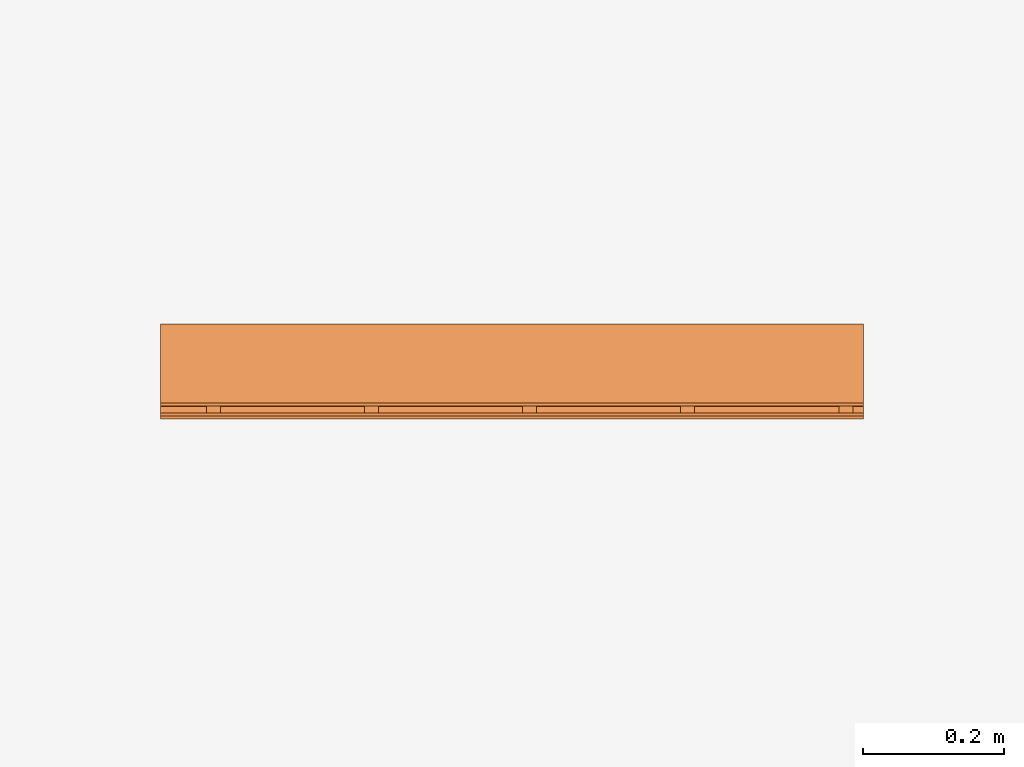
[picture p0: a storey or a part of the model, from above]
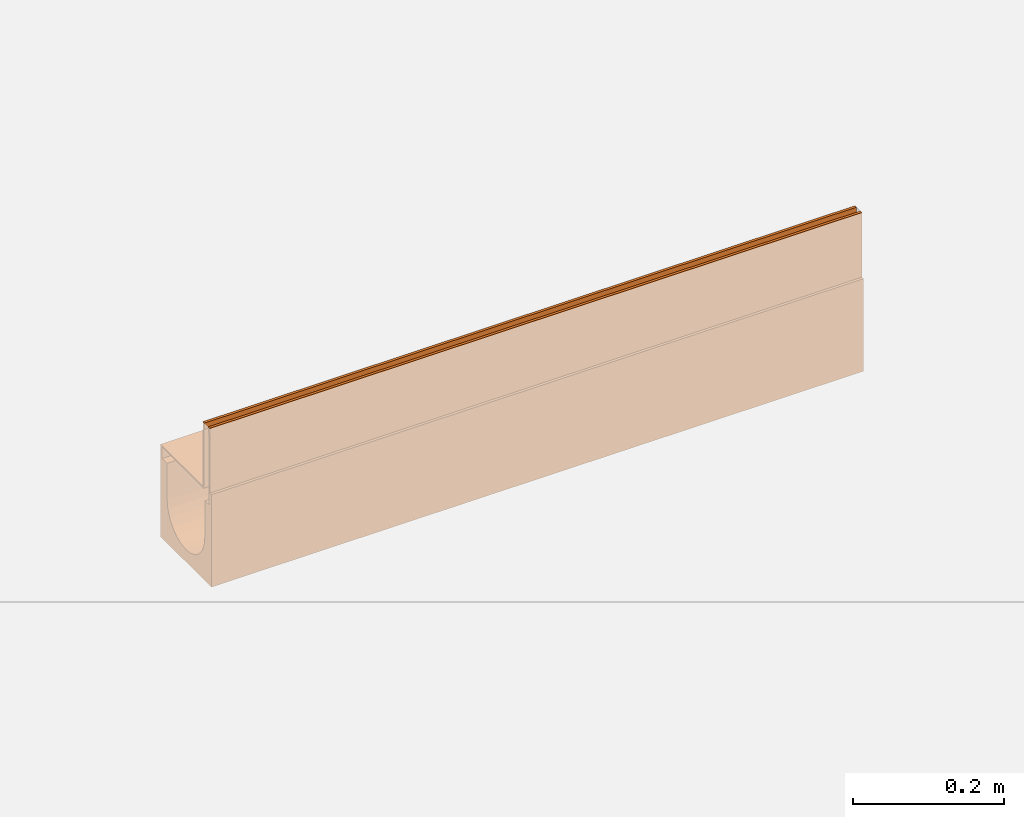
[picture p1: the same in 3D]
Properties of the parts of a building model (IFC2X3)

# File
Description: ViewDefinition [CoordinationView]
File name: 23000 - No 0.0 Constant Depth Channel - 1000mm LG - Invert Depth 130mm.ifc
Time: 2013-10-31T17:19:01
Written by: Autodesk Revit 2013
Made in: 20120221_2030(x64)

# IfcProject, Project Number
LongName: Project Name; Phase: Project Status

# IfcSite, Default
RefLatitude: 42, 21, 30, 344238; RefLongitude: -71, -3, -35, -194702; RefElevation: 0 mm

# IfcBuilding
Pset_BuildingCommon - NumberOfStoreys: 1
Other - Project Issue Date: Issue Date; Project Status: Project Status; Project Number: Project Number; Client Name: Owner; Project Name: Project Name; Project Address: ## Street City, State Zip

# IfcBuildingStorey, Level 1
LongName: Level 1; Elevation: 0 mm
Constraints - Elevation Base: 0; Elevation: 0 mm
Graphics - Line Weight: 1; Color: 0; Symbol at End 2 Default: yes; Symbol: M_Level Head - Circle: M_Level Head - Circle; Symbol at End 1 Default: no; Line Pattern: Center
Identity Data - Building Story: yes; Structural: no; Name: Level 1
Dimensions - Computation Height: 0 mm

# IfcBuildingElementProxy: 23000 - No 0.0 Constant Depth Channel - 1000mm LG - Invert Depth 130mm, Civil-Drainage-Channel-ACO-MultiDrain-M100D-Brickslot-Channel-System:23000 - No 0.0 Constant Depth Channel - 1000mm LG - Invert Depth 130mm:23000 - No 0.0 Constant Depth Channel - 1000mm LG - Invert Depth 130mm:196059
In: Level 1
Material: Steel, Galvanized, Vienite® Synthetic Resin Concrete
Phasing - Phase Created: New Construction
Constraints - Moves With Nearby Elements: no; Level: Level: Level 1
Construction - 23466_Load Class D400_Brickslot Grating_Galvanized Steel_500mm Long: no; 23461_Load Class C250_Brickslot Grating_Galvanized Steel_500mm Long: no; 23460_Load Class C250_Brickslot Grating_Galvanized Steel_1000mm Long: no; 23467_Load Class D400_Brickslot Access Unit_Galvanised Steel_500mm Long: no; 23462_Load Class C250_Brickslot Access Unit_Galvanised Steel_500mm Long: no; 23404_Universal Endcap (Male End): no; 23465_Load Class D400_Brickslot Grating_Galvanized Steel_1000mm Long: yes; 23404_Universal Endcap (Female End): no; Constant Depth Junction Channel: no; 23410_Sump Unit: no; Shallow Depth Channel with seal: no; Constant Depth Channel: yes; Sloping Channel: no; Shallow Depth Channel: no
Dimensions - FloorCut_Length: -1000 mm; Volume: 8492822 mm3; Brickslot Void Depth: 0 mm; Brickslot Access Unit Void Bottom Depth: -6605 mm; Brickslot Void Length: 1000 mm; Length: 1000 mm; EndCap Position: 1000 mm; Brickslot Access Unit Void Depth: -6500 mm; Custom_Void_length: 0 mm; ShallowOverallDepth: 100 mm; FloorCut_Width: 135 mm; Access_Custom_Void_Length: 0 mm; Length Drain: -1000 mm; Depth: 150 mm; InvDepth: 80 mm; Floor Cut Gap: 105 mm; SlopingEndOverallDepth: 250 mm; EndCap_Height: 150 mm; SlopingInvertDepth: 175 mm; SlopingEndInvertDepth: 180 mm; ShallowInvDepth: 80 mm; FloorCut_Depth: 150 mm; GratingLength: -1000 mm; Brickslot Access Unit Floor Cut Length: 500 mm; SlopingOverallDepth: 245 mm
Pset_BuildingElementProxyCommon - Reference: 23000 - No 0.0 Constant Depth Channel - 1000mm LG - Invert Depth 130mm
Identity Data - Product Page URL: http://www.aco.co.uk/product_detail.php?id=58; Product Code: 23000; Cost: 0; Watermarked With: BIM Manager Premium Suite; Manufacturer: ACO Technologies plc - ACO Water Management Division; e-mail Sales: customersupport@aco.co.uk; Price: POA - contact ACO; Assembly Code: D2040; Model Description: Channel drainage system; Fax: +44 (0)1462 815895; e-mail Technical: technical@aco.co.uk; Address: ACO Business Park, Hitchin Road, Shefford, Bedfordshire, United Kingdom SG17 5TE; Assembly Description: Rain Water Drainage; Product brochure: http://www.aco.co.uk/download.php?id=173; Watermark 1: This file is the property of ACO Technologies PLC; Maintenance guidelines: http://www.aco.co.uk/download.php?id=173; URL: www.aco.co.uk; Watermark 2: This file is water marked and users are prohibited to reproduce, adapt, distribute this information; Model: ACO MultiDrain MD Brickslot- M100D; Installation guidelines: http://www.aco.co.uk/download.php?id=173; Telephone: +44 (0)1462 816666; Type Comments: ACO MultiDrain M100D 0.0 Constant Depth Channel 1000mm Long; OmniClass Title: Rainwater Removal; OmniClass Number: 23.70.50.24
General - TagNumber: 0; SerialNumber: 0
Data - Product Dimensions: 1000mm x 135mm x 150mm (LxWxH); Hydraulic Performance: http://www.aco.co.uk/download.php?id=173; Concrete Surround Volume - Load Class D 400 - Concrete Pavement: 0.17m³/m; ACO Hydraulic Design Software: http://www.acodesign.co.uk; Concrete Surround Volume - Load Class B 125 - C 250 - Concrete Pavement: 0.11m³/m; Concrete Surround Volume - Load Class A 15 - Concrete Pavement: 0.07m³/m; Product Weight: 13.2 Kg; Product Standard: BS EN 1433:2002, CE marked; Pre-formed Outlet Ø: 110mm; Load Class: A 15 - D 400; Channel C.S.A: 0.009m²; Installation - Concrete Grade: Refer to brochure; Invert Depth: 130mm
Other - Revision: 1; Watermarked By: www.aco.co.uk; Created By: www.aco.co.uk
Model Properties - End Cap Product code 23404: No 306 Universal End Cap - 135mm wide x 300mm long - Spigot Ø110mm x 50mm long - Silver - Polypropylene - 0.16kg; Brickslot Access Unit Product code 23462: Load Class C250 - Brickslot Access Unit Galvanised Steel - 500mm long x 105mm high - 10mm Slot - Intake area - 10000mm²/m - 6.4 Kg; Brickslot Grating Product code 23466: Load Class D400 - Brickslot Galvanised Steel - 500mm long x 105mm high - 10mm Slot - Intake area - 10000mm²/m - 3.3 Kg; Brickslot Grating Product code 23460: Load Class C250 - Brickslot Galvanised Steel - 1000mm long x 105mm high - 10mm Slot - Intake area - 10000mm²/m - 6.6 Kg; Brickslot Access Unit Product code 23467: Load Class D400 - Brickslot Access Unit Galvanised Steel - 500mm long x 105mm high - 10mm Slot - Intake area - 10000mm²/m - 6.4 Kg; Brickslot Grating Product code 23461: Load Class C250 - Brickslot Galvanised Steel - 500mm long x 105mm high - 10mm Slot - Intake area - 10000mm²/m -3.3 Kg; Brickslot Grating Product code 23465: Load Class D400 - Brickslot Galvanised Steel - 1000mm long x 105mm high - 10mm Slot - Intake area - 10000mm²/m - 6.6 Kg
Green Building Properties - Channel Recycled Material Content: 20% minimum; Edge Rail Recyclable: Fully recyclable; Edge Rail Recycled Material Content: Between 40% - 90%; Channel Recyclable: Fully recyclable
Materials and Finishes - Channel Colour: Brown; Edge Rail Colour: Silver; Edge Rail Finish: Pre-galvanised; Edge Rail Material: Steel; Channel Material: Vienite® Synthetic Resin Concrete

# IfcOpeningElement: Recess (2)
In: Level 1
Dimensions - Volume: 24977860000 mm3; Thickness: 1000 mm; Perimeter: 20000 mm; Area: 25000000 mm2
Constraints - Related to Mass: no; Height Offset From Level: 0 mm; Level: Level: Level 1; Room Bounding: yes
Structural - Structural: no; Enable Analytical Model: no
Phasing - Phase Created: New Construction
Analytical Properties - Thermal mass: 1359800; Thermal Resistance (R): 1.19474; Heat Transfer Coefficient (U): 0.837; Absorptance: 0.1; Roughness: 1
Construction - Default Thickness: 1000 mm; Function: 0
Graphics - Coarse Scale Fill Color: 0
Materials and Finishes - Structural Material: Earth

# IfcSlab: Floor:Generic Floor - 1000mm, Floor:Generic Floor - 1000mm:193825
In: Level 1
PredefinedType: FLOOR; Material: Earth 1000 mm
Dimensions - Volume: 24977860000 mm3; Thickness: 1000 mm; Perimeter: 20000 mm; Area: 25000000 mm2
Constraints - Related to Mass: no; Height Offset From Level: 0 mm; Level: Level: Level 1; Room Bounding: yes
Structural - Structural: no; Enable Analytical Model: no
Phasing - Phase Created: New Construction
Pset_SlabCommon - Reference: Generic Floor - 1000mm; IsExternal: no; LoadBearing: yes
Analytical Properties - Thermal mass: 1359800; Thermal Resistance (R): 1.19474; Heat Transfer Coefficient (U): 0.837; Absorptance: 0.1; Roughness: 1
Construction - Default Thickness: 1000 mm; Function: 0
Graphics - Coarse Scale Fill Color: 0
Materials and Finishes - Structural Material: Earth
